VERSION 5.7 ;
  NOWIREEXTENSIONATPIN ON ;
  DIVIDERCHAR "/" ;
  BUSBITCHARS "[]" ;
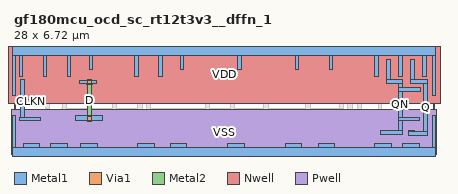
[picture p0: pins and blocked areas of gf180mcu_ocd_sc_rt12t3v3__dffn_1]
MACRO gf180mcu_ocd_sc_rt12t3v3__dffn_1
  CLASS CORE ;
  FOREIGN gf180mcu_ocd_sc_rt12t3v3__dffn_1 ;
  ORIGIN 0.000 0.000 ;
  SIZE 28.000 BY 6.720 ;
  SYMMETRY X Y ;
  SITE unithd ;
  PIN D
    DIRECTION INPUT ;
    USE SIGNAL ;
    ANTENNAGATEAREA 1.672300 ;
    PORT
      LAYER Metal1 ;
        RECT 4.850 4.770 5.230 4.790 ;
        RECT 4.340 4.540 5.480 4.770 ;
        RECT 4.850 4.530 5.230 4.540 ;
        RECT 4.130 2.075 5.890 2.405 ;
      LAYER Via1 ;
        RECT 4.910 4.530 5.170 4.790 ;
        RECT 4.910 2.105 5.170 2.365 ;
      LAYER Metal2 ;
        RECT 4.900 2.045 5.180 4.855 ;
    END
  END D
  PIN CLKN
    DIRECTION INPUT ;
    USE SIGNAL ;
    ANTENNAGATEAREA 1.672300 ;
    PORT
      LAYER Metal1 ;
        RECT 0.445 3.525 0.675 4.825 ;
        RECT 0.370 3.195 1.870 3.525 ;
        RECT 0.445 2.320 0.675 3.195 ;
        RECT 0.345 2.090 1.770 2.320 ;
    END
  END CLKN
  PIN Q
    DIRECTION OUTPUT ;
    USE SIGNAL ;
    ANTENNADIFFAREA 0.976900 ;
    PORT
      LAYER Metal1 ;
        RECT 26.445 4.820 26.675 6.180 ;
        RECT 26.445 4.560 27.570 4.820 ;
        RECT 26.290 1.380 26.670 1.425 ;
        RECT 27.310 1.380 27.570 4.560 ;
        RECT 26.290 1.120 27.570 1.380 ;
    END
  END Q
  PIN QN
    DIRECTION OUTPUT ;
    USE SIGNAL ;
    ANTENNAGATEAREA 1.672300 ;
    ANTENNADIFFAREA 0.976900 ;
    PORT
      LAYER Metal1 ;
        RECT 24.845 4.820 25.075 6.180 ;
        RECT 24.845 4.560 25.890 4.820 ;
        RECT 25.630 4.290 25.890 4.560 ;
        RECT 25.630 4.060 27.080 4.290 ;
        RECT 25.630 2.320 25.890 4.060 ;
        RECT 25.630 2.075 27.050 2.320 ;
        RECT 25.630 1.430 25.890 2.075 ;
        RECT 24.760 1.425 25.890 1.430 ;
        RECT 24.440 1.195 25.890 1.425 ;
    END
  END QN
  PIN VDD
    DIRECTION INOUT ;
    USE POWER ;
    SHAPE ABUTMENT ;
    PORT
      LAYER Nwell ;
        RECT -0.450 3.245 28.610 7.330 ;
      LAYER Metal1 ;
        RECT -0.115 6.420 28.115 7.020 ;
        RECT -0.115 3.745 0.115 6.420 ;
        RECT 0.365 5.060 0.595 6.420 ;
        RECT 1.965 5.060 2.195 6.420 ;
        RECT 3.565 5.065 3.795 6.420 ;
        RECT 5.005 5.520 5.235 6.420 ;
        RECT 8.045 5.060 8.275 6.420 ;
        RECT 9.645 5.045 9.875 6.420 ;
        RECT 11.085 5.520 11.315 6.420 ;
        RECT 14.925 5.520 15.155 6.420 ;
        RECT 18.765 5.520 18.995 6.420 ;
        RECT 21.005 5.520 21.235 6.420 ;
        RECT 24.045 5.060 24.275 6.420 ;
        RECT 25.645 5.060 25.875 6.420 ;
        RECT 27.245 5.065 27.475 6.420 ;
        RECT 27.885 3.750 28.115 6.420 ;
    END
  END VDD
  PIN VSS
    DIRECTION INOUT ;
    USE GROUND ;
    SHAPE ABUTMENT ;
    PORT
      LAYER Pwell ;
        RECT -0.180 -0.180 28.180 2.815 ;
      LAYER Metal1 ;
        RECT -0.115 0.300 0.115 2.410 ;
        RECT 0.600 0.300 1.710 0.585 ;
        RECT 2.450 0.300 3.560 0.585 ;
        RECT 4.460 0.300 5.570 0.585 ;
        RECT 8.255 0.300 9.365 0.585 ;
        RECT 10.410 0.300 11.520 0.585 ;
        RECT 14.250 0.300 15.360 0.585 ;
        RECT 18.085 0.300 19.195 0.585 ;
        RECT 20.270 0.300 21.380 0.585 ;
        RECT 24.060 0.300 25.170 0.585 ;
        RECT 25.910 0.300 27.020 0.585 ;
        RECT 27.885 0.300 28.115 2.410 ;
        RECT -0.115 -0.300 28.115 0.300 ;
    END
  END VSS
  OBS
      LAYER Metal1 ;
        RECT 1.165 4.820 1.395 6.180 ;
        RECT 2.765 4.820 2.995 6.180 ;
        RECT 4.205 5.290 4.435 6.190 ;
        RECT 5.805 5.960 7.635 6.190 ;
        RECT 8.845 6.070 9.075 6.160 ;
        RECT 5.805 5.290 6.035 5.960 ;
        RECT 4.205 5.060 6.035 5.290 ;
        RECT 6.590 4.975 6.850 5.730 ;
        RECT 7.405 5.055 7.635 5.960 ;
        RECT 8.830 5.065 9.090 6.070 ;
        RECT 10.285 5.290 10.515 6.190 ;
        RECT 11.885 5.960 13.715 6.190 ;
        RECT 11.885 5.290 12.115 5.960 ;
        RECT 1.165 4.560 2.535 4.820 ;
        RECT 2.765 4.560 3.550 4.820 ;
        RECT 6.605 4.770 6.850 4.975 ;
        RECT 2.110 4.540 2.535 4.560 ;
        RECT 5.985 4.540 6.375 4.770 ;
        RECT 6.605 4.540 7.945 4.770 ;
        RECT 8.195 4.565 8.585 4.830 ;
        RECT 8.835 4.770 9.065 5.065 ;
        RECT 10.285 5.060 12.115 5.290 ;
        RECT 12.685 5.000 13.010 5.730 ;
        RECT 13.485 5.055 13.715 5.960 ;
        RECT 14.125 5.290 14.355 6.190 ;
        RECT 15.725 5.960 17.555 6.190 ;
        RECT 15.725 5.290 15.955 5.960 ;
        RECT 14.125 5.060 15.955 5.290 ;
        RECT 16.525 5.720 16.765 5.730 ;
        RECT 14.255 4.770 14.825 4.805 ;
        RECT 2.110 4.300 2.370 4.540 ;
        RECT 6.090 4.300 6.320 4.540 ;
        RECT 2.110 4.070 7.935 4.300 ;
        RECT 2.110 2.885 2.370 4.070 ;
        RECT 7.705 3.455 7.935 4.070 ;
        RECT 8.270 4.290 8.500 4.565 ;
        RECT 8.835 4.540 11.735 4.770 ;
        RECT 11.980 4.540 12.930 4.770 ;
        RECT 14.255 4.540 15.245 4.770 ;
        RECT 12.045 4.290 12.275 4.540 ;
        RECT 16.010 4.290 16.240 4.825 ;
        RECT 16.525 4.770 16.930 5.720 ;
        RECT 17.325 5.055 17.555 5.960 ;
        RECT 17.965 5.290 18.195 6.180 ;
        RECT 19.565 5.730 19.795 6.180 ;
        RECT 19.470 5.290 19.795 5.730 ;
        RECT 17.965 5.065 19.795 5.290 ;
        RECT 20.205 5.290 20.435 6.190 ;
        RECT 21.805 5.960 23.635 6.190 ;
        RECT 21.805 5.290 22.035 5.960 ;
        RECT 17.965 5.060 19.730 5.065 ;
        RECT 20.205 5.060 22.035 5.290 ;
        RECT 19.470 4.770 19.730 5.060 ;
        RECT 22.270 4.980 22.835 5.725 ;
        RECT 23.405 5.055 23.635 5.960 ;
        RECT 16.525 4.540 18.860 4.770 ;
        RECT 19.470 4.540 20.985 4.770 ;
        RECT 21.255 4.520 23.150 4.750 ;
        RECT 21.255 4.290 21.485 4.520 ;
        RECT 8.270 4.060 21.485 4.290 ;
        RECT 21.730 4.060 22.690 4.290 ;
        RECT 7.705 3.225 9.055 3.455 ;
        RECT 2.110 2.555 2.365 2.885 ;
        RECT 3.170 2.875 3.550 2.905 ;
        RECT 8.825 2.875 9.055 3.225 ;
        RECT 21.730 2.875 21.960 4.060 ;
        RECT 3.170 2.645 8.585 2.875 ;
        RECT 8.825 2.645 21.960 2.875 ;
        RECT 2.110 2.320 2.370 2.555 ;
        RECT 7.265 2.325 7.510 2.645 ;
        RECT 8.200 2.610 8.585 2.645 ;
        RECT 12.690 2.385 13.070 2.415 ;
        RECT 2.110 2.090 3.495 2.320 ;
        RECT 6.400 2.095 7.510 2.325 ;
        RECT 9.540 2.320 13.070 2.385 ;
        RECT 13.375 2.375 13.650 2.645 ;
        RECT 7.750 2.150 13.070 2.320 ;
        RECT 7.750 2.090 9.770 2.150 ;
        RECT 13.310 2.145 13.740 2.375 ;
        RECT 16.255 2.325 16.490 2.645 ;
        RECT 22.210 2.345 22.625 2.375 ;
        RECT 22.920 2.350 23.150 4.520 ;
        RECT 24.280 4.060 25.400 4.290 ;
        RECT 14.300 2.090 15.535 2.320 ;
        RECT 16.165 2.095 17.100 2.325 ;
        RECT 19.200 2.320 22.625 2.345 ;
        RECT 17.340 2.115 22.625 2.320 ;
        RECT 22.860 2.120 23.695 2.350 ;
        RECT 24.285 2.320 24.515 4.060 ;
        RECT 17.340 2.090 19.600 2.115 ;
        RECT 24.225 2.090 25.370 2.320 ;
        RECT 2.110 1.425 2.370 2.090 ;
        RECT 3.170 1.425 3.550 1.440 ;
        RECT 6.010 1.425 6.240 1.815 ;
        RECT 0.980 1.195 2.370 1.425 ;
        RECT 2.830 1.195 3.550 1.425 ;
        RECT 4.840 1.195 6.240 1.425 ;
        RECT 3.170 1.180 3.550 1.195 ;
        RECT 6.010 0.770 6.240 1.195 ;
        RECT 6.590 1.440 6.850 1.840 ;
        RECT 7.750 1.440 8.010 2.090 ;
        RECT 14.300 1.995 14.690 2.090 ;
        RECT 14.300 1.915 14.620 1.995 ;
        RECT 6.590 1.180 8.010 1.440 ;
        RECT 8.770 1.425 9.150 1.830 ;
        RECT 10.000 1.685 14.620 1.915 ;
        RECT 10.000 1.425 10.230 1.685 ;
        RECT 11.960 1.425 12.190 1.455 ;
        RECT 8.635 1.195 10.230 1.425 ;
        RECT 10.790 1.195 12.190 1.425 ;
        RECT 6.590 0.720 6.850 1.180 ;
        RECT 8.770 0.815 9.150 1.195 ;
        RECT 10.000 0.770 10.230 1.195 ;
        RECT 11.960 0.770 12.190 1.195 ;
        RECT 12.690 0.770 13.085 1.455 ;
        RECT 15.800 1.425 16.030 1.815 ;
        RECT 16.670 1.560 16.930 1.620 ;
        RECT 16.670 1.480 16.945 1.560 ;
        RECT 14.630 1.195 16.030 1.425 ;
        RECT 15.800 0.770 16.030 1.195 ;
        RECT 16.640 1.425 16.945 1.480 ;
        RECT 17.340 1.425 17.600 2.090 ;
        RECT 24.225 1.885 24.475 2.090 ;
        RECT 19.860 1.655 24.475 1.885 ;
        RECT 19.860 1.425 20.090 1.655 ;
        RECT 16.640 1.195 17.600 1.425 ;
        RECT 18.465 1.195 20.090 1.425 ;
        RECT 20.650 1.195 22.040 1.425 ;
        RECT 16.640 1.140 16.945 1.195 ;
        RECT 16.670 1.010 16.945 1.140 ;
        RECT 16.670 0.950 16.930 1.010 ;
        RECT 19.410 0.980 20.090 1.195 ;
        RECT 19.410 0.815 19.790 0.980 ;
        RECT 21.810 0.740 22.040 1.195 ;
        RECT 22.270 1.165 22.965 1.395 ;
        RECT 22.270 0.755 22.595 1.165 ;
      LAYER Via1 ;
        RECT 6.590 5.035 6.850 5.645 ;
        RECT 8.830 5.125 9.090 6.005 ;
        RECT 3.230 4.560 3.490 4.820 ;
        RECT 8.265 4.565 8.525 4.830 ;
        RECT 12.750 5.065 13.010 5.670 ;
        RECT 16.670 5.050 16.930 5.660 ;
        RECT 14.430 4.540 14.690 4.805 ;
        RECT 19.470 4.945 19.730 5.670 ;
        RECT 22.270 5.040 22.530 5.665 ;
        RECT 3.230 2.645 3.490 2.905 ;
        RECT 8.265 2.610 8.525 2.875 ;
        RECT 12.750 2.150 13.010 2.415 ;
        RECT 3.230 1.180 3.490 1.440 ;
        RECT 6.590 0.785 6.850 1.775 ;
        RECT 14.430 2.055 14.690 2.320 ;
        RECT 22.270 2.115 22.530 2.375 ;
        RECT 8.830 0.815 9.090 1.830 ;
        RECT 12.750 0.770 13.025 1.455 ;
        RECT 19.470 0.815 19.730 1.415 ;
        RECT 22.270 0.815 22.530 1.335 ;
      LAYER Metal2 ;
        RECT 3.220 1.120 3.500 4.880 ;
        RECT 6.580 0.720 6.860 5.705 ;
        RECT 8.255 2.545 8.535 4.890 ;
        RECT 8.820 0.745 9.100 6.075 ;
        RECT 12.740 1.955 13.020 5.735 ;
        RECT 14.420 1.995 14.700 4.880 ;
        RECT 12.740 0.700 13.035 1.955 ;
        RECT 16.660 0.950 16.940 5.720 ;
        RECT 19.460 1.005 19.740 5.740 ;
        RECT 19.455 0.700 19.740 1.005 ;
        RECT 22.260 0.755 22.540 5.770 ;
  END
END gf180mcu_ocd_sc_rt12t3v3__dffn_1
END LIBRARY

